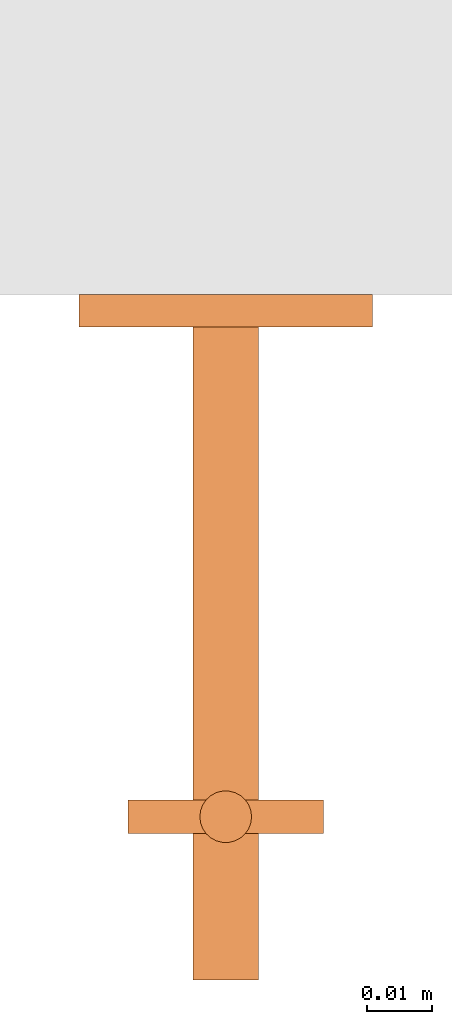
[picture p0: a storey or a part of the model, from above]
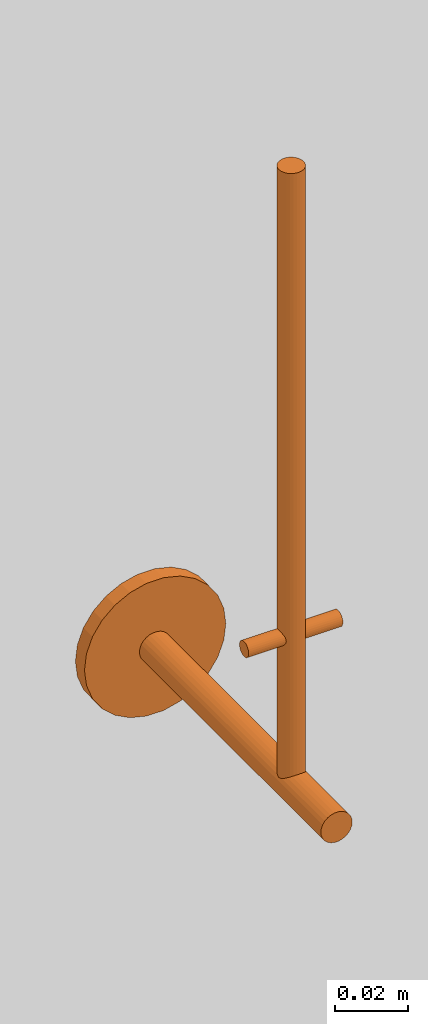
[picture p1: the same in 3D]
Properties of the parts of a building model (IFC2X3)

# File
Description: ViewDefinition [CoordinationView]
Time: 2016-09-26T11:56:16
Written by: The EXPRESS Data Manager Version 5.01.0100.02.64mod : 6 Jun 2012
Made in: 20140709_2115(x64) - Exporter 2014.0.2014.0709 - Default UI
Comment: STEP Physical File produced by: The EXPRESS Data Manager Version 5.01.0100.02.64mod : 6 Jun 2012 * Module: EDMstepFileFactory/EDMstandAlone * Creation date: Mon Sep 26 11:56:16 2016 * Host: BIM-HP * Database: C:\Users\dcole\AppData\Local\Temp\{C98C0DB6-BBDD-4934-B4B5-8D10C44E7934}\ifc * Database version: 5507 * Database creation date: Mon Sep 26 11:56:14 2016 * Schema: IFC2X3 * Model: DataRepository.ifc * Model creation date: Mon Sep 26 11:56:15 2016 * Header model: DataRepository.ifc_HeaderModel * Header model creation date: Mon Sep 26 11:56:15 2016 * EDMuser: sdai-user * EDMgroup: sdai-group * License ID and type: 5605 : Permanent license. Expiry date: * EDMstepFileFactory options: 020000

# IfcProject
LongName: P:\Fastrack\53721_BELL-CHEM\ADDITIONAL DRAWINGS 2016 BIM\IFC\DP2102-DP2103.ifc

# IfcSite, Default
RefLatitude: 42, 24, 53, 508911; RefLongitude: -71, -15, -29, -58837; RefElevation: 0 mm

# IfcBuilding
Pset_BuildingCommon - NumberOfStoreys: 1

# IfcBuildingStorey, Level 1
LongName: Level 1; Elevation: 0 mm
Constraints - Elevation Base: Project Base Point; Elevation: 0 mm
Identity Data - Name: Level 1; Structural: no; Building Story: yes
Dimensions - Computation Height: 0 mm
Graphics - Symbol at End 1 Default: no; Symbol at End 2 Default: yes; Color: 0; Line Weight: 1; Line Pattern: -3000010

# IfcBuildingElementProxy: DP2102 / DP2103 Dolphin Spare Toilet Roll Holder, DP2102 - DP2103:DP2102 / DP2103 Dolphin Spare Toilet Roll Holder:22067
In: Level 1
Material: Stainless Steel
Phasing - Phase Created: New Construction
Dimensions - Volume: 0.0000270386 m3; Width: Base Diameter 45mm; Projection: 105mm; Height: DP2102 = 230mm DP2103 = 330mm
Constraints - Offset: 96.6944 mm; Host: Level : Level 1; Level: Level: Level 1; Moves With Nearby Elements: no
Pset_ManufacturerTypeInformation - Manufacturer: Dolphin Solutions Ltd.
Pset_BuildingElementProxyCommon - Reference: DP2102 / DP2103 Dolphin Spare Toilet Roll Holder
Identity Data - Tel No.: +44 (0) 1424 202 224; Fax No.: +44 (0) 1424 205 200; URL: www.dolphinsolutions.co.uk; Description: Spare toilet roll holder; Manufacturer: Dolphin Solutions Ltd.; Email: info@dolphinsolutions.co.uk; Model: DP2102 / DP2103; Assembly Code: D2010900; Assembly Description: Other Plumbing Fixtures; Address: Southpoint, Compass Park, Bodiam, Robertsbridge, TN32 5BS
General - Product Page Link: https://www.dolphinsolutions.co.uk/product/spare-toilet-roll-holder-7/; Product Data: Superior quality and timeless design for prestigious washrooms. Easy-care 18/10 chrome nickel stainless steel. Anti-theft, robust four-point fixing. Holds 2 or 3 spare toilet rolls.

# IfcWallStandardCase: Basic Wall:Wall 1, Basic Wall:Wall 1:3092
In: Level 1
Type - PredefinedType: STANDARD; Material: Default Wall 50 mm
Type - Graphics - Coarse Scale Fill Color: 8454143
Type - Construction - Function: Exterior; Wrapping at Inserts: Do not wrap; Width: 50 mm
Type - Analytical Properties - Roughness: 1; Absorptance: 0.1
Dimensions - Length: 415 mm; Volume: 0.0230627 m3; Area: 0.461253 m2
Constraints - Location Line: Finish Face: Interior; Room Bounding: yes; Top Extension Distance: 0 mm; Base Constraint: Level: Level 1; Base is Attached: no; Base Extension Distance: 0 mm; Top Offset: 0 mm; Base Offset: -336.835 mm; Unconnected Height: 1111.45 mm; Top is Attached: no; Related to Mass: no
Structural - Structural: no; Structural Usage: Non-bearing; Enable Analytical Model: no
Phasing - Phase Created: New Construction
Pset_WallCommon - Reference: Wall 1; LoadBearing: no; ExtendToStructure: no; IsExternal: yes
